One B-rep face of a CAD part: STEP entity #78462.
In plain terms, the planar face has unit normal (0, 0, 1).
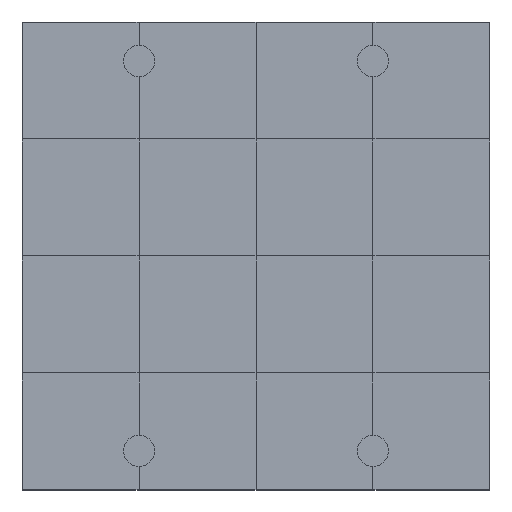
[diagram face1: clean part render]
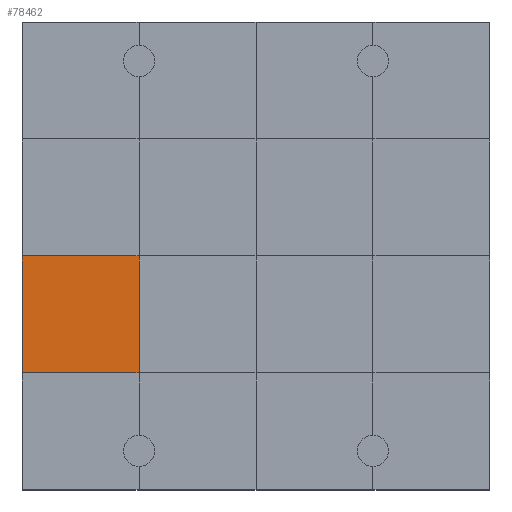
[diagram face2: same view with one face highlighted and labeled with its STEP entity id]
Its self-contained STEP definition (entity closure, numbers rounded to 3 decimals):
#78012 = VERTEX_POINT('',#78013);
#78013 = CARTESIAN_POINT('',(0.,3.,1.2));
#78027 = PLANE('',#78028);
#78028 = AXIS2_PLACEMENT_3D('',#78029,#78030,#78031);
#78029 = CARTESIAN_POINT('',(0.,3.,0.));
#78030 = DIRECTION('',(1.,0.,-0.));
#78031 = DIRECTION('',(0.,0.,1.));
#78053 = PLANE('',#78054);
#78054 = AXIS2_PLACEMENT_3D('',#78055,#78056,#78057);
#78055 = CARTESIAN_POINT('',(0.,0.,1.2));
#78056 = DIRECTION('',(0.,0.,1.));
#78057 = DIRECTION('',(1.,0.,-0.));
#78204 = VERTEX_POINT('',#78205);
#78205 = CARTESIAN_POINT('',(3.,3.,1.2));
#78226 = EDGE_CURVE('',#78012,#78204,#78227,.T.);
#78227 = SURFACE_CURVE('',#78228,(#78232,#78239),.PCURVE_S1.);
#78228 = LINE('',#78229,#78230);
#78229 = CARTESIAN_POINT('',(0.,3.,1.2));
#78230 = VECTOR('',#78231,1.);
#78231 = DIRECTION('',(1.,0.,-0.));
#78232 = PCURVE('',#78053,#78233);
#78233 = DEFINITIONAL_REPRESENTATION('',(#78234),#78238);
#78234 = LINE('',#78235,#78236);
#78235 = CARTESIAN_POINT('',(0.,3.));
#78236 = VECTOR('',#78237,1.);
#78237 = DIRECTION('',(1.,0.));
#78238 = ( GEOMETRIC_REPRESENTATION_CONTEXT(2) 
PARAMETRIC_REPRESENTATION_CONTEXT() REPRESENTATION_CONTEXT('2D SPACE',''
  ) );
#78239 = PCURVE('',#78240,#78245);
#78240 = PLANE('',#78241);
#78241 = AXIS2_PLACEMENT_3D('',#78242,#78243,#78244);
#78242 = CARTESIAN_POINT('',(0.,3.,1.2));
#78243 = DIRECTION('',(0.,0.,1.));
#78244 = DIRECTION('',(1.,0.,-0.));
#78245 = DEFINITIONAL_REPRESENTATION('',(#78246),#78250);
#78246 = LINE('',#78247,#78248);
#78247 = CARTESIAN_POINT('',(0.,0.));
#78248 = VECTOR('',#78249,1.);
#78249 = DIRECTION('',(1.,0.));
#78250 = ( GEOMETRIC_REPRESENTATION_CONTEXT(2) 
PARAMETRIC_REPRESENTATION_CONTEXT() REPRESENTATION_CONTEXT('2D SPACE',''
  ) );
#78285 = VERTEX_POINT('',#78286);
#78286 = CARTESIAN_POINT('',(0.,6.,1.2));
#78312 = EDGE_CURVE('',#78012,#78285,#78313,.T.);
#78313 = SURFACE_CURVE('',#78314,(#78318,#78325),.PCURVE_S1.);
#78314 = LINE('',#78315,#78316);
#78315 = CARTESIAN_POINT('',(0.,3.,1.2));
#78316 = VECTOR('',#78317,1.);
#78317 = DIRECTION('',(-0.,1.,0.));
#78318 = PCURVE('',#78027,#78319);
#78319 = DEFINITIONAL_REPRESENTATION('',(#78320),#78324);
#78320 = LINE('',#78321,#78322);
#78321 = CARTESIAN_POINT('',(1.2,0.));
#78322 = VECTOR('',#78323,1.);
#78323 = DIRECTION('',(0.,-1.));
#78324 = ( GEOMETRIC_REPRESENTATION_CONTEXT(2) 
PARAMETRIC_REPRESENTATION_CONTEXT() REPRESENTATION_CONTEXT('2D SPACE',''
  ) );
#78325 = PCURVE('',#78240,#78326);
#78326 = DEFINITIONAL_REPRESENTATION('',(#78327),#78331);
#78327 = LINE('',#78328,#78329);
#78328 = CARTESIAN_POINT('',(0.,0.));
#78329 = VECTOR('',#78330,1.);
#78330 = DIRECTION('',(0.,1.));
#78331 = ( GEOMETRIC_REPRESENTATION_CONTEXT(2) 
PARAMETRIC_REPRESENTATION_CONTEXT() REPRESENTATION_CONTEXT('2D SPACE',''
  ) );
#78462 = ADVANCED_FACE('',(#78463),#78240,.T.);
#78463 = FACE_BOUND('',#78464,.T.);
#78464 = EDGE_LOOP('',(#78465,#78466,#78467,#78495));
#78465 = ORIENTED_EDGE('',*,*,#78312,.F.);
#78466 = ORIENTED_EDGE('',*,*,#78226,.T.);
#78467 = ORIENTED_EDGE('',*,*,#78468,.T.);
#78468 = EDGE_CURVE('',#78204,#78469,#78471,.T.);
#78469 = VERTEX_POINT('',#78470);
#78470 = CARTESIAN_POINT('',(3.,6.,1.2));
#78471 = SURFACE_CURVE('',#78472,(#78476,#78483),.PCURVE_S1.);
#78472 = LINE('',#78473,#78474);
#78473 = CARTESIAN_POINT('',(3.,3.,1.2));
#78474 = VECTOR('',#78475,1.);
#78475 = DIRECTION('',(-0.,1.,0.));
#78476 = PCURVE('',#78240,#78477);
#78477 = DEFINITIONAL_REPRESENTATION('',(#78478),#78482);
#78478 = LINE('',#78479,#78480);
#78479 = CARTESIAN_POINT('',(3.,0.));
#78480 = VECTOR('',#78481,1.);
#78481 = DIRECTION('',(0.,1.));
#78482 = ( GEOMETRIC_REPRESENTATION_CONTEXT(2) 
PARAMETRIC_REPRESENTATION_CONTEXT() REPRESENTATION_CONTEXT('2D SPACE',''
  ) );
#78483 = PCURVE('',#78484,#78489);
#78484 = PLANE('',#78485);
#78485 = AXIS2_PLACEMENT_3D('',#78486,#78487,#78488);
#78486 = CARTESIAN_POINT('',(3.,3.,1.2));
#78487 = DIRECTION('',(0.,0.,1.));
#78488 = DIRECTION('',(1.,0.,-0.));
#78489 = DEFINITIONAL_REPRESENTATION('',(#78490),#78494);
#78490 = LINE('',#78491,#78492);
#78491 = CARTESIAN_POINT('',(0.,0.));
#78492 = VECTOR('',#78493,1.);
#78493 = DIRECTION('',(0.,1.));
#78494 = ( GEOMETRIC_REPRESENTATION_CONTEXT(2) 
PARAMETRIC_REPRESENTATION_CONTEXT() REPRESENTATION_CONTEXT('2D SPACE',''
  ) );
#78495 = ORIENTED_EDGE('',*,*,#78496,.F.);
#78496 = EDGE_CURVE('',#78285,#78469,#78497,.T.);
#78497 = SURFACE_CURVE('',#78498,(#78502,#78509),.PCURVE_S1.);
#78498 = LINE('',#78499,#78500);
#78499 = CARTESIAN_POINT('',(0.,6.,1.2));
#78500 = VECTOR('',#78501,1.);
#78501 = DIRECTION('',(1.,0.,-0.));
#78502 = PCURVE('',#78240,#78503);
#78503 = DEFINITIONAL_REPRESENTATION('',(#78504),#78508);
#78504 = LINE('',#78505,#78506);
#78505 = CARTESIAN_POINT('',(0.,3.));
#78506 = VECTOR('',#78507,1.);
#78507 = DIRECTION('',(1.,0.));
#78508 = ( GEOMETRIC_REPRESENTATION_CONTEXT(2) 
PARAMETRIC_REPRESENTATION_CONTEXT() REPRESENTATION_CONTEXT('2D SPACE',''
  ) );
#78509 = PCURVE('',#78510,#78515);
#78510 = PLANE('',#78511);
#78511 = AXIS2_PLACEMENT_3D('',#78512,#78513,#78514);
#78512 = CARTESIAN_POINT('',(0.,6.,1.2));
#78513 = DIRECTION('',(0.,0.,1.));
#78514 = DIRECTION('',(1.,0.,-0.));
#78515 = DEFINITIONAL_REPRESENTATION('',(#78516),#78520);
#78516 = LINE('',#78517,#78518);
#78517 = CARTESIAN_POINT('',(0.,0.));
#78518 = VECTOR('',#78519,1.);
#78519 = DIRECTION('',(1.,0.));
#78520 = ( GEOMETRIC_REPRESENTATION_CONTEXT(2) 
PARAMETRIC_REPRESENTATION_CONTEXT() REPRESENTATION_CONTEXT('2D SPACE',''
  ) );
